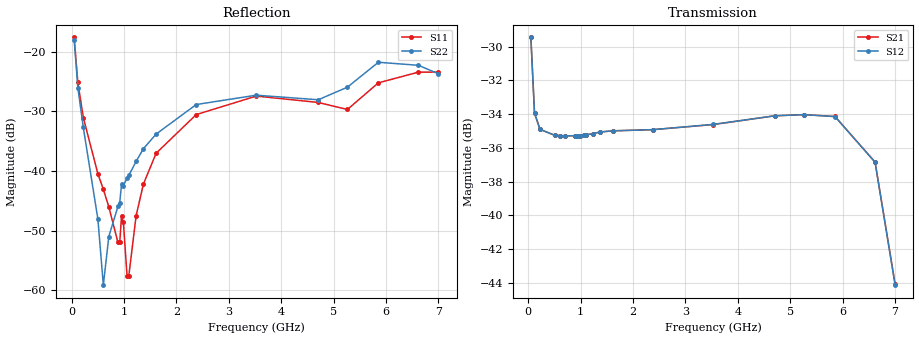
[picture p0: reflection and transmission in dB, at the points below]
! Integrated Device Technology
! Corporate Headquarters
! 6024 Silver Creek Valley Road
! San Jose, CA 95138  USA
! Phone:  1-408-284-8200
! Toll Free:  1-800-223-1366
! Webpage:  http://www.idt.com/
! Timing and RF Division
! 515 Groton Road, Suite 102
! Westford, MA 01886-6024
! Device:  F2258
! Description: Voltage Variable RF Attenuator
! Frequency:  50.0 -  6000.00 MHz
! Package:  3x3 mm Thin QFN Plastic Package: 16 pin
! Ports:  2 RF, 2 DC
!  Pin  1  = NC
!  Pin  2  = NC
!  Pin  3  = RF2  = Port 2
!  Pin  4  = GND
!  Pin  5  = Vdd
!  Pin  6  = NC
!  Pin  7  = VCTRL
!  Pin  8  = NC
!  Pin  9  = GND
!  Pin 10  = RF1  = Port 1
!  Pin 11  = NC
!  Pin 12  = NC
!  Pin 13  = NC
!  Pin 14  = NC
!  Pin 15  = NC
!  Pin 16  = NC
! Vcntrl:  2.130 Volts
! Vdd:  +3.300 Volts
! Current:  1.152 mA
! Data:  The device was measured on a the F2258 evaluation board which has
!  individual transmission lines to the RF pins.  Data was collected
!  using a calibrated network analyzer.  The evaluation board was
!  de-embedded using a TRL calibration technique.
!  The reference plane is the edge of the package pin.
! Misc:  SN 10
!  Action Tracker AT0285
! Date Measured:  2014-12-10
! Date:  2016-01-13  MJV
! Note:
!  Integrated Device Technology supplies this data as a sample of measured
!  data at the package pin for this product.  Your particular data for this
!  product may vary.
!  Data was taken at 25 degrees C.
!  Integrated Device Technology reserves the right to change this data at anytime.
!Freq_(GHz)  S11M_(dB)  S11P_(deg)  S21M_(dB)  S21P_(deg)  S12M_(dB)  S12P_(deg)  S22M_(dB)  S22P_(deg)
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# GHz S dB R 50
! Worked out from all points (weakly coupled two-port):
!   201 points, 50 MHz to 7 GHz, reference 50 ohm
!   highest |S21| = -29.46 dB at 50 MHz (marker M1); lowest = -44.0 dB at 7 GHz (marker M2)
!   lowest |S11| = -57.6 dB at 1.058 GHz (marker M3), VSWR 1.00, Z = 49.9 + j0.0604 ohm
!   |S11| at or under -10 dB: start of sweep to end of sweep
!   |S22| runs from -59.2 to -18.1 dB; largest |S21 - S12| = 8.4e-05
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0.05  -17.55 -111.0  -29.46 -67.8  -29.46 -67.8  -18.07 -110.3
0.1195  -25.12 -106.9  -33.94 -36.5  -33.94 -36.5  -26.02 -102.7
0.22375  -31.03 -110.7  -34.90 -21.1  -34.90 -21.1  -32.68 -101.1
0.50175  -40.46 -121.8  -35.25 -11.2  -35.25 -11.2  -48.08 -85.3
0.606  -43.09 -125.9  -35.27 -10.0  -35.28 -10.0  -59.17 -28.1
0.71025  -46.01 -137.5  -35.29 -9.3  -35.29 -9.2  -51.01 59.7
0.884  -51.99 166.5  -35.28 -8.5  -35.28 -8.5  -45.96 73.5
0.91875  -51.99 151.0  -35.27 -8.4  -35.28 -8.4  -45.29 73.7
0.9535  -47.54 -163.2  -35.28 -8.3  -35.28 -8.3  -42.23 96.6
0.98825  -48.63 -173.9  -35.27 -8.2  -35.27 -8.2  -42.48 93.1
1.05775  -57.56 152.8  -35.25 -8.1  -35.25 -8.1  -41.20 77.6
1.0925  -57.56 120.9  -35.23 -8.0  -35.23 -8.0  -40.74 74.5
1.2315  -47.50 46.6  -35.16 -8.1  -35.16 -8.1  -38.38 57.4
1.3705  -42.19 37.3  -35.06 -8.5  -35.06 -8.5  -36.25 49.6
1.61375  -37.01 32.9  -34.99 -9.8  -34.99 -9.8  -33.79 40.8
2.37825  -30.52 48.1  -34.92 -13.5  -34.92 -13.5  -28.83 36.3
3.525  -27.41 91.6  -34.62 -20.0  -34.61 -20.0  -27.26 62.4
4.7065  -28.48 95.6  -34.10 -29.2  -34.10 -29.2  -28.03 54.0
5.2625  -29.66 54.3  -34.03 -35.3  -34.03 -35.3  -25.92 16.6
5.85325  -25.19 29.8  -34.14 -45.9  -34.15 -45.9  -21.73 -5.4
6.61775  -23.39 49.7  -36.84 -68.6  -36.85 -68.7  -22.24 -46.8
7  -23.38 84.4  -44.05 -62.0  -44.12 -61.6  -23.66 -129.2
